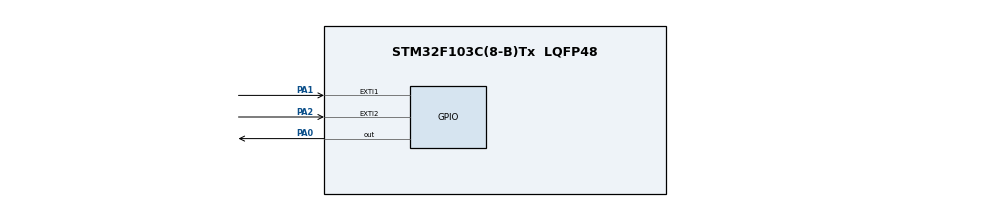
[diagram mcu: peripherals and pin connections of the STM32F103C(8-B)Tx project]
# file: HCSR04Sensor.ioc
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Mcu.Family=STM32F1
Mcu.Name=STM32F103C(8-B)Tx
Mcu.Package=LQFP48
NVIC.EXTI1_IRQn=true\:1\:0\:true\:false\:true\:true\:true\:true
NVIC.EXTI2_IRQn=true\:1\:0\:true\:false\:true\:true\:true\:true
NVIC.PriorityGroup=NVIC_PRIORITYGROUP_4
PA0-WKUP.Signal=GPIO_Output
PA1.GPIO_ModeDefaultEXTI=GPIO_MODE_IT_RISING_FALLING
PA1.Signal=GPXTI1
PA13.Mode=Serial_Wire
PA13.Signal=SYS_JTMS-SWDIO
PA14.Mode=Serial_Wire
PA14.Signal=SYS_JTCK-SWCLK
PA2.Signal=GPXTI2
PD0-OSC_IN.Mode=HSE-External-Oscillator
PD0-OSC_IN.Signal=RCC_OSC_IN
PD1-OSC_OUT.Mode=HSE-External-Oscillator
PD1-OSC_OUT.Signal=RCC_OSC_OUT
ProjectManager.HeapSize=0x200
ProjectManager.StackSize=0x400
ProjectManager.TargetToolchain=MDK-ARM V5.32
RCC.APB1Freq_Value=8000000
RCC.APB2Freq_Value=8000000
TIM1.Prescaler=71
VP_TIM1_VS_ClockSourceINT.Mode=Internal
board=custom

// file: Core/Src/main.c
/* USER CODE BEGIN Header */
/**
  ******************************************************************************
  * @file           : main.c
  * @brief          : Main program body
  ******************************************************************************
  * @attention
  *
  * <h2><center>&copy; Copyright (c) 2021 STMicroelectronics.
  * All rights reserved.</center></h2>
  *
  * This software component is licensed by ST under BSD 3-Clause license,
  * the "License"; You may not use this file except in compliance with the
  * License. You may obtain a copy of the License at:
  *                        opensource.org/licenses/BSD-3-Clause
  *
  ******************************************************************************
  */
/* USER CODE END Header */
#include "main.h"

/* USER CODE BEGIN Includes */
#include "hcsr04.h"
/* USER CODE END Includes */

TIM_HandleTypeDef htim1;

void SystemClock_Config(void);
static void MX_GPIO_Init(void);
static void MX_TIM1_Init(void);

/* USER CODE BEGIN 0 */
float value_kc;
void HC04_Complete_Callback(float kc)
{
	value_kc = kc;
}
/* USER CODE END 0 */

int main(void)
{

  /* MCU Configuration--------------------------------------------------------*/

  /* Reset of all peripherals, Initializes the Flash interface and the Systick. */
  HAL_Init();

  /* Configure the system clock */
  SystemClock_Config();

  /* Initialize all configured peripherals */
  MX_GPIO_Init();
  MX_TIM1_Init();
  /* USER CODE BEGIN 2 */
	hc04_init(&htim1);
  /* USER CODE END 2 */

  /* Infinite loop */
  while (1)
  {

    /* USER CODE BEGIN 3 */
		uint32_t t_get_distance;
		if(HAL_GetTick() - t_get_distance >= 300)
		{
			HC04_Start();
			t_get_distance = HAL_GetTick();
		}
		HC04_Handle();
  }
  /* USER CODE END 3 */
}

void SystemClock_Config(void)
{
  RCC_OscInitTypeDef RCC_OscInitStruct = {0};
  RCC_ClkInitTypeDef RCC_ClkInitStruct = {0};

  /** Initializes the RCC Oscillators according to the specified parameters
  * in the RCC_OscInitTypeDef structure.
  */
  RCC_OscInitStruct.OscillatorType = RCC_OSCILLATORTYPE_HSI;
  RCC_OscInitStruct.HSIState = RCC_HSI_ON;
  RCC_OscInitStruct.HSICalibrationValue = RCC_HSICALIBRATION_DEFAULT;
  RCC_OscInitStruct.PLL.PLLState = RCC_PLL_ON;
  RCC_OscInitStruct.PLL.PLLSource = RCC_PLLSOURCE_HSI_DIV2;
  RCC_OscInitStruct.PLL.PLLMUL = RCC_PLL_MUL16;
  if (HAL_RCC_OscConfig(&RCC_OscInitStruct) != HAL_OK)
  {
    Error_Handler();
  }
  /** Initializes the CPU, AHB and APB buses clocks
  */
  RCC_ClkInitStruct.ClockType = RCC_CLOCKTYPE_HCLK|RCC_CLOCKTYPE_SYSCLK
                              |RCC_CLOCKTYPE_PCLK1|RCC_CLOCKTYPE_PCLK2;
  RCC_ClkInitStruct.SYSCLKSource = RCC_SYSCLKSOURCE_PLLCLK;
  RCC_ClkInitStruct.AHBCLKDivider = RCC_SYSCLK_DIV1;
  RCC_ClkInitStruct.APB1CLKDivider = RCC_HCLK_DIV2;
  RCC_ClkInitStruct.APB2CLKDivider = RCC_HCLK_DIV1;

  if (HAL_RCC_ClockConfig(&RCC_ClkInitStruct, FLASH_LATENCY_2) != HAL_OK)
  {
    Error_Handler();
  }
}

static void MX_TIM1_Init(void)
{

  TIM_ClockConfigTypeDef sClockSourceConfig = {0};
  TIM_MasterConfigTypeDef sMasterConfig = {0};

  htim1.Instance = TIM1;
  htim1.Init.Prescaler = 71;
  htim1.Init.CounterMode = TIM_COUNTERMODE_UP;
  htim1.Init.Period = 65535;
  htim1.Init.ClockDivision = TIM_CLOCKDIVISION_DIV1;
  htim1.Init.RepetitionCounter = 0;
  htim1.Init.AutoReloadPreload = TIM_AUTORELOAD_PRELOAD_DISABLE;
  if (HAL_TIM_Base_Init(&htim1) != HAL_OK)
  {
    Error_Handler();
  }
  sClockSourceConfig.ClockSource = TIM_CLOCKSOURCE_INTERNAL;
  if (HAL_TIM_ConfigClockSource(&htim1, &sClockSourceConfig) != HAL_OK)
  {
    Error_Handler();
  }
  sMasterConfig.MasterOutputTrigger = TIM_TRGO_RESET;
  sMasterConfig.MasterSlaveMode = TIM_MASTERSLAVEMODE_DISABLE;
  if (HAL_TIMEx_MasterConfigSynchronization(&htim1, &sMasterConfig) != HAL_OK)
  {
    Error_Handler();
  }

}

static void MX_GPIO_Init(void)
{
  GPIO_InitTypeDef GPIO_InitStruct = {0};

  /* GPIO Ports Clock Enable */
  __HAL_RCC_GPIOA_CLK_ENABLE();

  /*Configure GPIO pin Output Level */
  HAL_GPIO_WritePin(GPIOA, GPIO_PIN_0, GPIO_PIN_RESET);

  /*Configure GPIO pin : PA0 */
  GPIO_InitStruct.Pin = GPIO_PIN_0;
  GPIO_InitStruct.Mode = GPIO_MODE_OUTPUT_PP;
  GPIO_InitStruct.Pull = GPIO_NOPULL;
  GPIO_InitStruct.Speed = GPIO_SPEED_FREQ_LOW;
  HAL_GPIO_Init(GPIOA, &GPIO_InitStruct);

  /*Configure GPIO pin : PA1 */
  GPIO_InitStruct.Pin = GPIO_PIN_1;
  GPIO_InitStruct.Mode = GPIO_MODE_IT_RISING_FALLING;
  GPIO_InitStruct.Pull = GPIO_PULLUP;
  HAL_GPIO_Init(GPIOA, &GPIO_InitStruct);

  /* EXTI interrupt init*/
  HAL_NVIC_SetPriority(EXTI1_IRQn, 1, 0);
  HAL_NVIC_EnableIRQ(EXTI1_IRQn);

}

void Error_Handler(void)
{
  __disable_irq();
  while (1)
  {
  }
}

/************************ (C) COPYRIGHT STMicroelectronics *****END OF FILE****/
